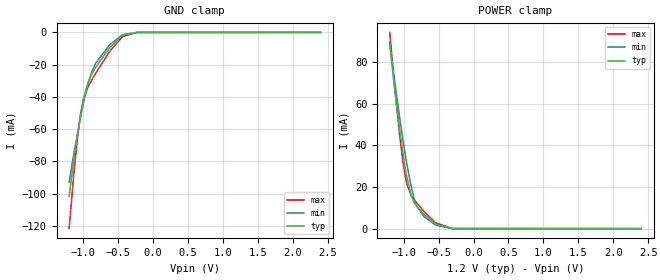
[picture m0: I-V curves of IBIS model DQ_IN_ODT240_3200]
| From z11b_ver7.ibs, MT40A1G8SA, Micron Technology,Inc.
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| MODEL DQ_IN_ODT240_3200 (Data Input with 240ohm ODT, 1600-3200Mbps)
[Model]   DQ_IN_ODT240_3200
Model_type   Input
Vinl = 905.000mV
Vinh = 1015.000mV
|   typ   min   max
|C_comp   0.807pF   0.756pF   0.859pF
C_comp_power_clamp   0.4035pF   0.3780pF   0.4295pF
C_comp_gnd_clamp   0.4035pF   0.3780pF   0.4295pF
| Note: C_comp changes when the ODT circuit is enabled.
|[Model Spec]
| Dynamic Overshoot Parameters from DDR4 Specification
|D_overshoot_ampl_h   0.40   NA   NA
|D_overshoot_ampl_l   0.40   NA   NA
|D_overshoot_area_h   0.0800n   NA   NA
|D_overshoot_area_l   0.0800n   NA   NA
[Voltage Range]   1.2000V   1.1400V   1.2600V
| Junction Temperature (Ambient temp is 35C typ, 95C min, 0C max)
[Temperature Range]   50.0   110.0   0.0
[Add Submodel]
| Submodel Name   Mode
240ohm_ODT_3200   Non-Driving
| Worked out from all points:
|   GND clamp passes 1 mA (typ) near -0.39 V on its own axis
|   POWER clamp passes 1 mA (typ) near -0.48 V on its own axis
[GND_clamp]
|   Voltage   I(typ)   I(min)   I(max)
-1.2V     -101.7mA   -92.84mA   -121.7mA
-1.135V   -79.96mA   -75.84mA   -88.92mA
-1.08V    -63.49mA   -62.76mA   -65.41mA
-1.036V   -51.56mA   -52.83mA   -50.65mA
-992.7mV  -41.38mA   -43.57mA   -41.02mA
-927.3mV  -30.76mA   -31.6mA    -33.57mA
-872.7mV  -25.55mA   -24.13mA   -29.29mA
-818.2mV  -21.61mA   -19.01mA   -25.29mA
-621.8mV  -9.66mA    -7.8mA     -11.96mA
-436.4mV  -1.915mA   -1.476mA   -2.607mA
-229.1mV  -17.62uA   -20.1uA    -21.35uA
2.4V      0A         0A         0A
[POWER_clamp]
|   Voltage   I(typ)   I(min)   I(max)
-1.2V     88.79mA    89.61mA    94.2mA
-1.135V   68.71mA    72.12mA    70.03mA
-1.058V   47.63mA    53.55mA    44.95mA
-1.004V   34.46mA    41.11mA    30.27mA
-960mV    25.41mA    31.92mA    21.99mA
-894.5mV  16.02mA    20.41mA    16.03mA
-850.9mV  12.63mA    14.54mA    13.97mA
-807.3mV  10.5mA     10.53mA    12.15mA
-709.1mV  6.91mA     5.769mA    8.279mA
-545.5mV  2.224mA    1.735mA    2.842mA
-305.5mV  24.75uA    26.66uA    31.49uA
2.4V      0A         0A         0A
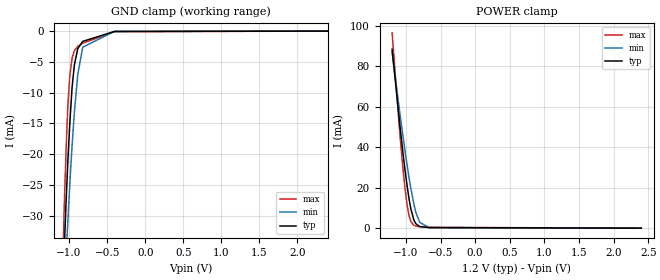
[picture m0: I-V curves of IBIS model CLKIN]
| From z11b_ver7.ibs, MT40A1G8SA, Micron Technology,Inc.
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| MODEL CLKIN (Clock Input Model, 1600-3200Mbps)
[Model]   CLKIN
Model_type   Input
Vinl = 510.000mV
Vinh = 690.000mV
|   typ   min   max
|C_comp   0.350pF   0.300pF   0.400pF
C_comp_power_clamp   0.1750pF   0.1500pF   0.2000pF
C_comp_gnd_clamp   0.1750pF   0.1500pF   0.2000pF
[Model Spec]
| Input threshold voltage corners
Vinl   0.5100V   0.4800V   0.5400V
Vinh   0.6900V   0.6600V   0.7200V
| Dynamic Overshoot Parameters from DDR4 Specification
|D_overshoot_ampl_h   0.30   NA   NA
|D_overshoot_ampl_l   0.30   NA   NA
|D_overshoot_area_h   0.0775n   NA   NA
|D_overshoot_area_l   0.0762n   NA   NA
[Receiver Thresholds]
|Vth   =  0.600V
|Vth_min  =  0.5880V
|Vth_max  =  0.6120V
|Vinh_ac  =  0.090V
|Vinh_dc  =  0.060V
|Vinl_ac  = -0.090V
|Vinl_dc  = -0.060V
|Tslew_ac =  5.000ns |Not specified, so set to high value
|Threshold_sensitivity = 0.50
|Reference_supply Power_clamp_ref
|NOTE: If using the IBISCHK 4.2.1 or older parser, Differential receiver
|threshold parameters must be commented out because the parser generates
|errors for multiple differential models.
Vcross_low   = 0.460V
Vcross_high  = 0.740V
Vdiff_ac   = 180mV
Vdiff_dc   = 150mV
Tdiffslew_ac = 10.000ns |Not specified, so set to high value
[Voltage Range]   1.2000V   1.1400V   1.2600V
[POWER Clamp Reference]   1.2000V   1.1400V   1.2600V
| Junction Temperature (Ambient temp is 35C typ, 95C min, 0C max)
[Temperature Range]   50.0   110.0   0.0
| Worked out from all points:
|   GND clamp passes 1 mA (typ) near -0.71 V on its own axis
|   POWER clamp passes 1 mA (typ) near -0.82 V on its own axis
[GND Clamp]
|   Voltage   I(typ)   I(min)   I(max)
-1.2V     -88.24mA   -82.12mA   -111.1mA
-1.08V    -41.31mA   -47.46mA   -36.47mA
-1.06V    -34.46mA   -42.1mA    -27.08mA
-1.035V   -26.55mA   -35.62mA   -17.92mA
-1.015V   -20.87mA   -30.7mA    -11.91mA
-990mV    -14.98mA   -24.86mA   -7.246mA
-960mV    -9.118mA   -18.59mA   -4.383mA
-930mV    -5.482mA   -13.16mA   -3.169mA
-885mV    -2.833mA   -7.006mA   -2.468mA
-820mV    -1.672mA   -2.616mA   -1.978mA
-405mV    -65.37uA   -44.46uA   -101.2uA
2.4V      0A         0A         0A
[POWER Clamp]
|   Voltage   I(typ)   I(min)   I(max)
-1.2V     88.32mA    86.89mA    96.39mA
-1.09V    51.55mA    57.33mA    47.47mA
-1.05V    39.18mA    47.11mA    31.81mA
-1.015V   29.08mA    38.51mA    19.95mA
-985mV    21.39mA    31.49mA    11.78mA
-955mV    14.41mA    24.89mA    6.161mA
-930mV    9.647mA    19.79mA    3.38mA
-885mV    3.971mA    11.81mA    1.405mA
-855mV    2.12mA     7.623mA    1.01mA
-800mV    777.1uA    2.838mA    730.9uA
-665mV    276.1uA    268.7uA    398.3uA
2.4V      0A         0A         0A
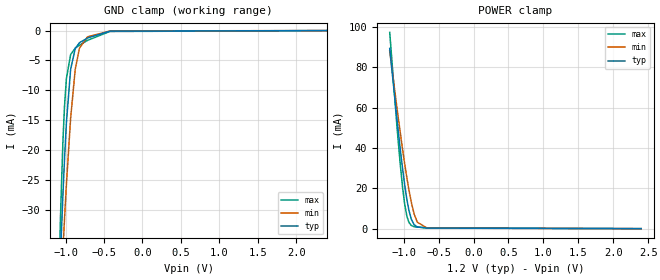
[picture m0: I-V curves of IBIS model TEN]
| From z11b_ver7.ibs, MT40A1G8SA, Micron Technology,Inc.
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| MODEL TEN (TEN Input Model)
[Model]   TEN
Model_type   Input
Vinl = 240.000mV
Vinh = 960.000mV
|   typ   min   max
|C_comp   0.250pF   0.200pF   0.300pF
C_comp_power_clamp   0.1250pF   0.1000pF   0.1500pF
C_comp_gnd_clamp   0.1250pF   0.1000pF   0.1500pF
[Model Spec]
| Input threshold voltage corners
Vinl   0.2400V   0.2280V   0.2520V
Vinh   0.9600V   0.9120V   1.0080V
[Voltage Range]   1.2000V   1.1400V   1.2600V
| Junction Temperature (Ambient temp is 35C typ, 95C min, 0C max)
[Temperature Range]   50.0   110.0   0.0
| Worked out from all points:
|   GND clamp passes 1 mA (typ) near -0.67 V on its own axis
|   POWER clamp passes 1 mA (typ) near -0.81 V on its own axis
[GND Clamp]
|   Voltage   I(typ)   I(min)   I(max)
-1.2V     -89.68mA   -83.76mA   -112.5mA
-1.08V    -42.27mA   -48.6mA    -37.43mA
-1.065V   -37.02mA   -44.48mA   -30.24mA
-1.035V   -27.36mA   -36.67mA   -18.41mA
-1.015V   -21.61mA   -31.62mA   -12.71mA
-990mV    -15.4mA    -25.73mA   -8.028mA
-935mV    -6.48mA    -14.64mA   -4.005mA
-875mV    -2.985mA   -6.456mA   -2.943mA
-820mV    -2.025mA   -2.921mA   -2.441mA
-715mV    -1.243mA   -1.044mA   -1.636mA
-425mV    -95.71uA   -64.44uA   -150uA
2.4V      0A         0A         0A
[POWER Clamp]
|   Voltage   I(typ)   I(min)   I(max)
-1.2V     89.29mA    88mA       97.25mA
-1.095V   53.78mA    59.42mA    50.04mA
-1.05V    39.66mA    47.81mA    32.16mA
-1.015V   29.47mA    39.09mA    20.17mA
-985mV    21.54mA    31.96mA    11.96mA
-955mV    14.57mA    25.34mA    6.252mA
-925mV    9.043mA    19.2mA     3.084mA
-890mV    4.569mA    12.96mA    1.546mA
-850mV    1.945mA    7.193mA    981.4uA
-805mV    853.4uA    3.217mA    763.2uA
-665mV    277.9uA    269.6uA    403.6uA
2.4V      0A         0A         0A
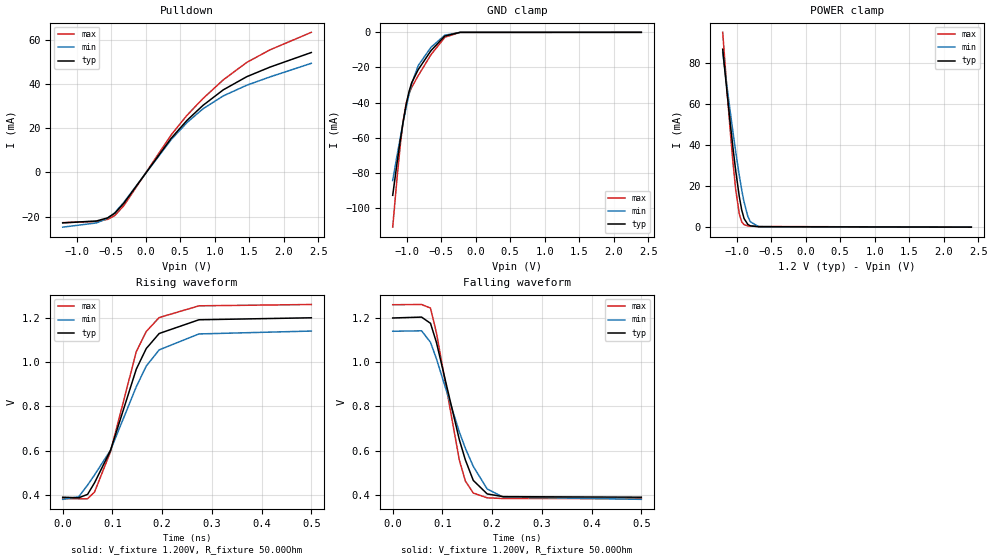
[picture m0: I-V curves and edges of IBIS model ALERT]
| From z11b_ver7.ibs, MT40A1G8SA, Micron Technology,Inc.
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| MODEL ALERT (ALERT_n Output Model, 1600-3200Mbps)
[Model]   ALERT
Model_type   Open_sink
Vmeas = 960.000mV
Vref = 1200.000mV
Cref = 0.0pF
Rref = 50.000Ohm
|   typ   min   max
|C_comp   0.750pF   0.700pF   0.800pF
C_comp_pulldown   0.7500pF   0.7000pF   0.8000pF
[Model Spec]
| Timing spec test load voltage corners
Vref   1.2000V   1.1400V   1.2600V
[Voltage Range]   1.2000V   1.1400V   1.2600V
| Junction Temperature (Ambient temp is 35C typ, 95C min, 0C max)
[Temperature Range]   50.0   110.0   0.0
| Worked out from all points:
|   slope of the pulldown table from 0 to 0.18 V, typ, clamps not added: 23.2 ohm
|   GND clamp passes 1 mA (typ) near -0.39 V on its own axis
|   POWER clamp passes 1 mA (typ) near -0.82 V on its own axis
|   falling waveform, V_fixture 1.200V, R_fixture 50.00Ohm: 20-80 % time 53.4ps typ, 69.5ps min, 42ps max; typ from 1.2 V to 0.389 V
|   rising waveform, V_fixture 1.200V, R_fixture 50.00Ohm: 20-80 % time 75.2ps typ, 91.2ps min, 64.2ps max; typ from 0.389 V to 1.2 V
[Pulldown]
|   Voltage   I(typ)   I(min)   I(max)
-1.2V     -22.83mA   -24.77mA   -22.73mA
-710mV    -21.97mA   -22.85mA   -22.24mA
-550mV    -20.56mA   -20.75mA   -21.25mA
-445mV    -18.46mA   -18.23mA   -19.49mA
-315mV    -13.93mA   -13.52mA   -15.03mA
370mV     15.46mA    14.85mA    16.99mA
600mV     23.61mA    22.62mA    25.92mA
830mV     30.36mA    28.81mA    33.45mA
1.125V    37.43mA    34.68mA    41.95mA
1.465V    43.38mA    39.52mA    49.85mA
1.8V      47.71mA    43.27mA    55.52mA
2.4V      54.34mA    49.44mA    63.48mA
[GND Clamp]
|   Voltage   I(typ)   I(min)   I(max)
-1.2V     -92.7mA    -84.28mA   -110.8mA
-1.135V   -73.71mA   -69.62mA   -81.94mA
-1.09V    -61.32mA   -59.85mA   -64.11mA
-1.05V    -51.11mA   -51.5mA    -50.88mA
-1.005V   -41.07mA   -42.68mA   -40.37mA
-965mV    -33.87mA   -35.53mA   -34.98mA
-925mV    -28.66mA   -29.21mA   -31.31mA
-830mV    -21.17mA   -18.86mA   -24.58mA
-645mV    -10.38mA   -8.47mA    -12.68mA
-445mV    -2.105mA   -1.62mA    -2.796mA
-225mV    -13.23uA   -29.17uA   -25.92uA
2.4V      0A         0A         0A
[POWER Clamp]
|   Voltage   I(typ)   I(min)   I(max)
-1.2V     86.56mA    84.96mA    94.75mA
-1.135V   64.78mA    67.59mA    65.46mA
-1.09V    50.35mA    55.92mA    46.44mA
-1.05V    38.17mA    45.87mA    30.97mA
-1.01V    26.98mA    36.26mA    17.79mA
-960mV    14.89mA    25.1mA     6.469mA
-925mV    8.372mA    18.1mA     2.608mA
-890mV    4.13mA     12.07mA    1.192mA
-835mV    1.286mA    5.127mA    602.2uA
-800mV    650.9uA    2.612mA    484.6uA
-680mV    216.2uA    235.1uA    312.5uA
2.4V      0A         0A         0A
[Ramp]
R_load = 50.00Ohm
|   typ   min   max
dV/dt_r   486.353mV/75.189ps  456.137mV/91.163ps  526.220mV/64.185ps
dV/dt_f   486.353mV/53.402ps  456.137mV/69.520ps  526.220mV/42.021ps
[Falling Waveform]
V_fixture = 1.200V
V_fixture_min = 1.140V
V_fixture_max = 1.260V
R_fixture = 50.00Ohm
|   Time   V(typ)   V(min)   V(max)
0s        1.2V       1.14V      1.26V
58ps      1.204V     1.142V     1.261V
76ps      1.176V     1.09V      1.245V
88ps      1.089V     1.015V     1.132V
134ps     649.4mV    684.6mV    557.2mV
146ps     558.9mV    611.4mV    463.1mV
162ps     465.5mV    528.9mV    408.3mV
190ps     404.2mV    426.5mV    386.6mV
222ps     392mV      390.1mV    383.5mV
500ps     389.4mV    379.8mV    383mV
[Rising Waveform]
V_fixture = 1.200V
V_fixture_min = 1.140V
V_fixture_max = 1.260V
R_fixture = 50.00Ohm
|   Time   V(typ)   V(min)   V(max)
0s        389.4mV    379.8mV    383mV
32ps      386.7mV    391.1mV    382.4mV
50ps      402.1mV    444mV      382.4mV
64ps      454.4mV    490mV      412.7mV
96ps      600.3mV    601mV      594.1mV
148ps     968mV      888.4mV    1.047V
168ps     1.061V     981.9mV    1.138V
194ps     1.129V     1.055V     1.201V
274ps     1.191V     1.127V     1.254V
500ps     1.2V       1.14V      1.26V
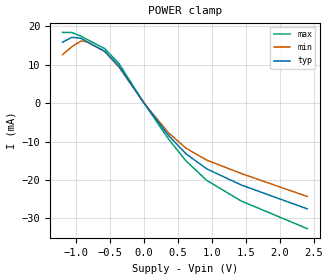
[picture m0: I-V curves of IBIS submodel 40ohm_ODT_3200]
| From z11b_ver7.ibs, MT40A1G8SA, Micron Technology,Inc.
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| SUBMODEL 40ohm_ODT_3200
[Submodel]   40ohm_ODT_3200
Submodel_type  Dynamic_clamp
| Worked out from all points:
|   POWER clamp passes 1 mA (typ) near -0.04 V on its own axis
[POWER Clamp]
|   Voltage   I(typ)   I(min)   I(max)
-1.2V     15.88mA    12.62mA    18.44mA
-1.065V   17.15mA    14.67mA    18.42mA
-930mV    16.94mA    16.19mA    17.48mA
-845mV    16.03mA    16.03mA    16.66mA
-580mV    13.54mA    13.47mA    14.23mA
-370mV    9.654mA    9.398mA    10.33mA
0V        66.76nA    68.51nA    78.99nA
360mV     -8.422mA   -7.744mA   -9.356mA
615mV     -13.16mA   -11.7mA    -15mA
920mV     -17.08mA   -14.81mA   -20.08mA
1.43V     -21.3mA    -18.31mA   -25.47mA
2.4V      -27.51mA   -24.29mA   -32.66mA
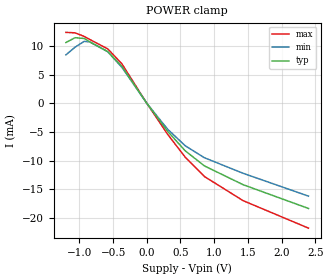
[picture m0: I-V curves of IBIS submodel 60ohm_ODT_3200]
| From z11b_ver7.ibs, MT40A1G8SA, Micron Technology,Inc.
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| SUBMODEL 60ohm_ODT_3200
[Submodel]   60ohm_ODT_3200
Submodel_type  Dynamic_clamp
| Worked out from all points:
|   POWER clamp passes 1 mA (typ) near -0.06 V on its own axis
[POWER Clamp]
|   Voltage   I(typ)   I(min)   I(max)
-1.2V     10.59mA    8.445mA    12.36mA
-1.065V   11.43mA    9.774mA    12.28mA
-930mV    11.3mA     10.79mA    11.66mA
-845mV    10.69mA    10.69mA    11.11mA
-580mV    9.024mA    8.982mA    9.487mA
-370mV    6.438mA    6.267mA    6.886mA
0V        51.68nA    48.39nA    53.27nA
310mV     -4.9mA     -4.531mA   -5.424mA
570mV     -8.284mA   -7.406mA   -9.394mA
855mV     -10.92mA   -9.496mA   -12.77mA
1.43V     -14.2mA    -12.21mA   -16.98mA
2.4V      -18.34mA   -16.19mA   -21.77mA
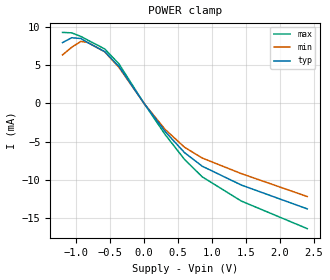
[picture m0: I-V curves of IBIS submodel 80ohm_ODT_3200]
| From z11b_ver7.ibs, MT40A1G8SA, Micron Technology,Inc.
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| SUBMODEL 80ohm_ODT_3200
[Submodel]   80ohm_ODT_3200
Submodel_type  Dynamic_clamp
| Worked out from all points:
|   POWER clamp passes 1 mA (typ) near -0.08 V on its own axis
[POWER Clamp]
|   Voltage   I(typ)   I(min)   I(max)
-1.2V     7.942mA    6.335mA    9.274mA
-1.065V   8.577mA    7.333mA    9.213mA
-930mV    8.477mA    8.099mA    8.748mA
-830mV    7.946mA    7.963mA    8.273mA
-580mV    6.772mA    6.74mA     7.119mA
-370mV    4.831mA    4.703mA    5.168mA
0V        40.32nA    37.49nA    44.84nA
310mV     -3.677mA   -3.4mA     -4.07mA
595mV     -6.423mA   -5.723mA   -7.305mA
855mV     -8.192mA   -7.123mA   -9.58mA
1.43V     -10.65mA   -9.158mA   -12.74mA
2.4V      -13.76mA   -12.15mA   -16.34mA
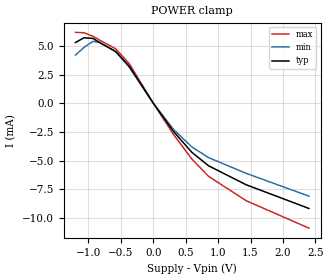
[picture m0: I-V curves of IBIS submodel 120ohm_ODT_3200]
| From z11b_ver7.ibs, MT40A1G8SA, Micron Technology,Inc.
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| SUBMODEL 120ohm_ODT_3200
[Submodel]   120ohm_ODT_3200
Submodel_type  Dynamic_clamp
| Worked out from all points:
|   POWER clamp passes 1 mA (typ) near -0.12 V on its own axis
[POWER Clamp]
|   Voltage   I(typ)   I(min)   I(max)
-1.2V     5.293mA    4.206mA    6.18mA
-1.07V    5.709mA    4.86mA     6.147mA
-930mV    5.651mA    5.398mA    5.831mA
-830mV    5.297mA    5.309mA    5.515mA
-580mV    4.514mA    4.493mA    4.746mA
-370mV    3.221mA    3.136mA    3.446mA
0V        30.43nA    22.74nA    36.21nA
310mV     -2.451mA   -2.267mA   -2.714mA
595mV     -4.282mA   -3.815mA   -4.87mA
855mV     -5.462mA   -4.749mA   -6.387mA
1.43V     -7.103mA   -6.106mA   -8.492mA
2.4V      -9.174mA   -8.101mA   -10.89mA
